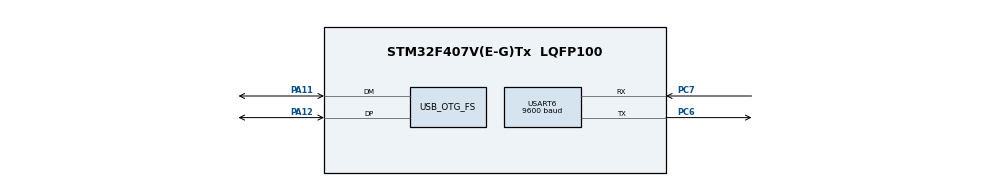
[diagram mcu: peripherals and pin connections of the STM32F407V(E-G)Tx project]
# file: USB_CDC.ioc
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Mcu.Family=STM32F4
Mcu.Name=STM32F407V(E-G)Tx
Mcu.Package=LQFP100
NVIC.OTG_FS_IRQn=true\:5\:0\:true\:false\:true\:false\:true\:true
NVIC.PriorityGroup=NVIC_PRIORITYGROUP_4
NVIC.USART6_IRQn=true\:3\:0\:true\:false\:true\:true\:true\:true
PA11.Mode=Device_Only
PA11.Signal=USB_OTG_FS_DM
PA12.Mode=Device_Only
PA12.Signal=USB_OTG_FS_DP
PA13.Mode=Serial_Wire
PA13.Signal=SYS_JTMS-SWDIO
PA14.Mode=Serial_Wire
PA14.Signal=SYS_JTCK-SWCLK
PC6.Mode=Asynchronous
PC6.Signal=USART6_TX
PC7.Mode=Asynchronous
PC7.Signal=USART6_RX
PH0-OSC_IN.Mode=HSE-External-Oscillator
PH0-OSC_IN.Signal=RCC_OSC_IN
PH1-OSC_OUT.Mode=HSE-External-Oscillator
PH1-OSC_OUT.Signal=RCC_OSC_OUT
ProjectManager.HeapSize=0x200
ProjectManager.StackSize=0x400
ProjectManager.TargetToolchain=STM32CubeIDE
RCC.48MHZClocksFreq_Value=48000000
RCC.AHBFreq_Value=168000000
RCC.APB1CLKDivider=RCC_HCLK_DIV4
RCC.APB1Freq_Value=42000000
RCC.APB1TimFreq_Value=84000000
RCC.APB2CLKDivider=RCC_HCLK_DIV2
RCC.APB2Freq_Value=84000000
RCC.APB2TimFreq_Value=168000000
RCC.CortexFreq_Value=168000000
RCC.HCLKFreq_Value=168000000
RCC.HSE_VALUE=25000000
RCC.HSI_VALUE=16000000
RCC.LSE_VALUE=32768
RCC.PLLM=25
RCC.PLLN=336
RCC.PLLQ=7
RCC.SYSCLKFreq_VALUE=168000000
RCC.SYSCLKSource=RCC_SYSCLKSOURCE_PLLCLK
RCC.VCOOutputFreq_Value=336000000
USART6.BaudRate=9600
USART6.VirtualMode=VM_ASYNC
USB_DEVICE.CLASS_NAME_FS=CDC
USB_DEVICE.VirtualMode-CDC_FS=Cdc
USB_DEVICE.VirtualModeFS=Cdc_FS
USB_OTG_FS.VirtualMode=Device_Only
VP_USB_DEVICE_VS_USB_DEVICE_CDC_FS.Mode=CDC_FS
board=custom

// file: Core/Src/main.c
/* USER CODE BEGIN Header */
/**
  ******************************************************************************
  * @file           : main.c
  * @brief          : Main program body
  ******************************************************************************
  * @attention
  *
  * Copyright (c) 2025 STMicroelectronics.
  * All rights reserved.
  *
  * This software is licensed under terms that can be found in the LICENSE file
  * in the root directory of this software component.
  * If no LICENSE file comes with this software, it is provided AS-IS.
  *
  ******************************************************************************
  */
/* USER CODE END Header */
#include "main.h"
#include "usb_device.h"

/* USER CODE BEGIN Includes */
#include <stdio.h>
#include "usbd_cdc_if.h"
/* USER CODE END Includes */

UART_HandleTypeDef huart6;

/* USER CODE BEGIN PV */
 uint8_t rxData = 0;
/* USER CODE END PV */

void SystemClock_Config(void);
static void MX_GPIO_Init(void);
static void MX_USART6_UART_Init(void);

int main(void)
{

  /* MCU Configuration--------------------------------------------------------*/

  /* Reset of all peripherals, Initializes the Flash interface and the Systick. */
  HAL_Init();

  /* Configure the system clock */
  SystemClock_Config();

  /* Initialize all configured peripherals */
  MX_GPIO_Init();
  MX_USB_DEVICE_Init();
  MX_USART6_UART_Init();
  /* USER CODE BEGIN 2 */
  HAL_NVIC_SetPriority(SysTick_IRQn, 0, 0);

  HAL_NVIC_SetPriority(USART6_IRQn, 3, 0);
  HAL_NVIC_EnableIRQ(USART6_IRQn);

  HAL_NVIC_SetPriority(OTG_FS_IRQn, 5, 0);
  HAL_NVIC_EnableIRQ(OTG_FS_IRQn);

  HAL_UART_Receive_IT(&huart6,&rxData,1);
  /* USER CODE END 2 */

  /* Infinite loop */
  /* USER CODE BEGIN WHILE */
  while (1)
  {
	  char usb_buffer[64];
	  int len = sprintf(usb_buffer, "RxData: %d (Char: %c)\r\n", rxData, rxData);
	  CDC_Transmit_FS((uint8_t*)usb_buffer, len);
    /* USER CODE END WHILE */

  }
}

void SystemClock_Config(void)
{
  RCC_OscInitTypeDef RCC_OscInitStruct = {0};
  RCC_ClkInitTypeDef RCC_ClkInitStruct = {0};

  /** Configure the main internal regulator output voltage
  */
  __HAL_RCC_PWR_CLK_ENABLE();
  __HAL_PWR_VOLTAGESCALING_CONFIG(PWR_REGULATOR_VOLTAGE_SCALE1);

  /** Initializes the RCC Oscillators according to the specified parameters
  * in the RCC_OscInitTypeDef structure.
  */
  RCC_OscInitStruct.OscillatorType = RCC_OSCILLATORTYPE_HSE;
  RCC_OscInitStruct.HSEState = RCC_HSE_ON;
  RCC_OscInitStruct.PLL.PLLState = RCC_PLL_ON;
  RCC_OscInitStruct.PLL.PLLSource = RCC_PLLSOURCE_HSE;
  RCC_OscInitStruct.PLL.PLLM = 8;
  RCC_OscInitStruct.PLL.PLLN = 336;
  RCC_OscInitStruct.PLL.PLLP = RCC_PLLP_DIV2;
  RCC_OscInitStruct.PLL.PLLQ = 7;
  if (HAL_RCC_OscConfig(&RCC_OscInitStruct) != HAL_OK)
  {
    Error_Handler();
  }

  /** Initializes the CPU, AHB and APB buses clocks
  */
  RCC_ClkInitStruct.ClockType = RCC_CLOCKTYPE_HCLK|RCC_CLOCKTYPE_SYSCLK
                              |RCC_CLOCKTYPE_PCLK1|RCC_CLOCKTYPE_PCLK2;
  RCC_ClkInitStruct.SYSCLKSource = RCC_SYSCLKSOURCE_PLLCLK;
  RCC_ClkInitStruct.AHBCLKDivider = RCC_SYSCLK_DIV1;
  RCC_ClkInitStruct.APB1CLKDivider = RCC_HCLK_DIV4;
  RCC_ClkInitStruct.APB2CLKDivider = RCC_HCLK_DIV2;

  if (HAL_RCC_ClockConfig(&RCC_ClkInitStruct, FLASH_LATENCY_5) != HAL_OK)
  {
    Error_Handler();
  }
}

static void MX_USART6_UART_Init(void)
{

  huart6.Instance = USART6;
  huart6.Init.BaudRate = 9600;
  huart6.Init.WordLength = UART_WORDLENGTH_8B;
  huart6.Init.StopBits = UART_STOPBITS_1;
  huart6.Init.Parity = UART_PARITY_NONE;
  huart6.Init.Mode = UART_MODE_TX_RX;
  huart6.Init.HwFlowCtl = UART_HWCONTROL_NONE;
  huart6.Init.OverSampling = UART_OVERSAMPLING_16;
  if (HAL_UART_Init(&huart6) != HAL_OK)
  {
    Error_Handler();
  }

}

static void MX_GPIO_Init(void)
{

  /* GPIO Ports Clock Enable */
  __HAL_RCC_GPIOH_CLK_ENABLE();
  __HAL_RCC_GPIOC_CLK_ENABLE();
  __HAL_RCC_GPIOA_CLK_ENABLE();

}

/* USER CODE BEGIN 4 */
void HAL_UART_RxCpltCallback(UART_HandleTypeDef *huart)
{
  if(huart->Instance==USART6)
  {
    if(rxData==78) // Ascii value of 'N' is 78 (N for NO)
    {
    	HAL_GPIO_WritePin(GPIOA, GPIO_PIN_1, 0);
    }
    else if (rxData==89) // Ascii value of 'Y' is 89 (Y for YES)
    {
    	HAL_GPIO_WritePin(GPIOA, GPIO_PIN_1, 1);
    }
    HAL_UART_Receive_IT(&huart6,&rxData, 1); // Enabling interrupt receive again
  }
}
/* USER CODE END 4 */

void Error_Handler(void)
{
  __disable_irq();
  while (1)
  {
  }
}
